VERSION 5.7 ;
  NOWIREEXTENSIONATPIN ON ;
  DIVIDERCHAR "/" ;
  BUSBITCHARS "[]" ;
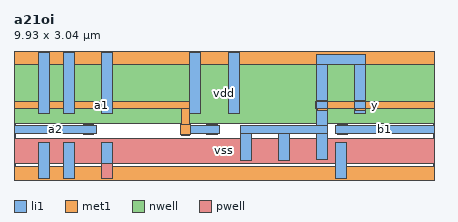
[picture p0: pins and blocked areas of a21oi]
MACRO a21oi
  CLASS BLOCK ;
  FOREIGN a21oi ;
  ORIGIN 7.160 1.570 ;
  SIZE 9.930 BY 3.040 ;
  PIN a1
    ANTENNAGATEAREA 0.585000 ;
    PORT
      LAYER li1 ;
        RECT -2.600 -0.280 -2.360 -0.250 ;
        RECT -3.200 -0.460 -2.310 -0.280 ;
        RECT -2.600 -0.490 -2.360 -0.460 ;
      LAYER met1 ;
        RECT -7.160 0.110 -3.020 0.290 ;
        RECT -3.200 -0.250 -3.020 0.110 ;
        RECT -3.230 -0.490 -2.990 -0.250 ;
        RECT -3.200 -0.520 -3.020 -0.490 ;
    END
  END a1
  PIN a2
    ANTENNAGATEAREA 0.585000 ;
    PORT
      LAYER li1 ;
        RECT -5.510 -0.280 -5.270 -0.250 ;
        RECT -7.160 -0.460 -5.220 -0.280 ;
        RECT -5.510 -0.490 -5.270 -0.460 ;
    END
  END a2
  PIN b1
    ANTENNAGATEAREA 0.517500 ;
    PORT
      LAYER li1 ;
        RECT 0.480 -0.280 0.720 -0.250 ;
        RECT 0.430 -0.460 2.770 -0.280 ;
        RECT 0.480 -0.490 0.720 -0.460 ;
    END
  END b1
  PIN vdd
    ANTENNADIFFAREA 1.500000 ;
    PORT
      LAYER nwell ;
        RECT -7.160 -0.230 2.770 1.160 ;
      LAYER li1 ;
        RECT -6.590 0.000 -6.330 1.440 ;
        RECT -6.000 0.000 -5.740 1.440 ;
        RECT -5.100 0.000 -4.840 1.440 ;
        RECT -3.000 0.000 -2.740 1.440 ;
        RECT -2.100 0.000 -1.840 1.440 ;
      LAYER met1 ;
        RECT -7.160 1.150 2.770 1.470 ;
    END
  END vdd
  PIN vss
    ANTENNADIFFAREA 0.540000 ;
    PORT
      LAYER pwell ;
        RECT -7.160 -1.180 2.770 -0.580 ;
        RECT -5.100 -1.540 -4.840 -1.180 ;
      LAYER li1 ;
        RECT -6.590 -1.540 -6.330 -0.690 ;
        RECT -6.000 -1.540 -5.740 -0.690 ;
        RECT -5.100 -1.540 -4.840 -0.690 ;
        RECT 0.450 -1.540 0.710 -0.680 ;
      LAYER met1 ;
        RECT -7.160 -1.570 2.770 -1.250 ;
    END
  END vss
  PIN y
    ANTENNADIFFAREA 1.005000 ;
    PORT
      LAYER li1 ;
        RECT 0.000 1.160 1.160 1.400 ;
        RECT 0.000 -0.280 0.260 1.160 ;
        RECT 0.900 0.000 1.160 1.160 ;
        RECT -1.800 -0.460 0.260 -0.280 ;
        RECT -1.800 -1.100 -1.540 -0.460 ;
        RECT -0.900 -1.100 -0.640 -0.460 ;
        RECT 0.000 -1.090 0.260 -0.460 ;
      LAYER met1 ;
        RECT 0.010 0.290 0.250 0.320 ;
        RECT 0.910 0.290 1.150 0.320 ;
        RECT -0.020 0.110 2.770 0.290 ;
        RECT 0.010 0.080 0.250 0.110 ;
        RECT 0.910 0.080 1.150 0.110 ;
    END
  END y
  OBS
      LAYER pwell ;
        RECT -3.200 -0.250 -3.020 -0.230 ;
        RECT -3.230 -0.490 -2.990 -0.250 ;
        RECT -3.200 -0.520 -3.020 -0.490 ;
        RECT -6.550 -1.500 -6.370 -1.320 ;
        RECT -5.960 -1.500 -5.780 -1.320 ;
      LAYER li1 ;
        RECT -5.550 0.000 -5.290 0.960 ;
        RECT -4.650 0.000 -4.390 0.960 ;
        RECT -2.550 0.000 -2.290 0.960 ;
        RECT -1.650 0.000 -1.390 0.960 ;
        RECT 0.450 0.000 0.710 0.960 ;
        RECT 1.350 0.000 1.610 0.960 ;
        RECT -5.550 -1.100 -5.290 -0.690 ;
        RECT -1.350 -1.100 -1.090 -0.690 ;
      LAYER met1 ;
        RECT -5.540 0.850 -5.300 0.880 ;
        RECT -4.640 0.850 -4.400 0.880 ;
        RECT -2.540 0.850 -2.300 0.880 ;
        RECT -1.640 0.850 -1.400 0.880 ;
        RECT 0.460 0.850 0.700 0.880 ;
        RECT 1.360 0.850 1.600 0.880 ;
        RECT -5.570 0.670 1.630 0.850 ;
        RECT -5.540 0.640 -5.300 0.670 ;
        RECT -4.640 0.640 -4.400 0.670 ;
        RECT -2.540 0.640 -2.300 0.670 ;
        RECT -1.640 0.640 -1.400 0.670 ;
        RECT 0.460 0.640 0.700 0.670 ;
        RECT 1.360 0.640 1.600 0.670 ;
        RECT -5.540 -0.790 -5.300 -0.760 ;
        RECT -1.340 -0.790 -1.100 -0.760 ;
        RECT -5.570 -0.970 -1.070 -0.790 ;
        RECT -5.540 -1.000 -5.300 -0.970 ;
        RECT -1.340 -1.000 -1.100 -0.970 ;
  END
END a21oi
END LIBRARY

